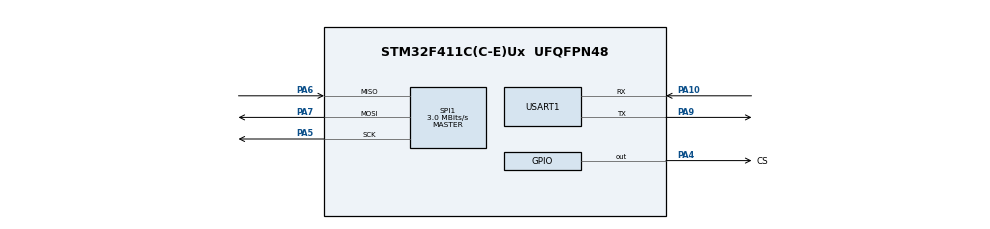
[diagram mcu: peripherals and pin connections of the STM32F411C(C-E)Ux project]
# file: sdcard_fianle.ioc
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Dma.Request0=SPI1_RX
Dma.Request1=SPI1_TX
Dma.SPI1_RX.0.Direction=DMA_PERIPH_TO_MEMORY
Dma.SPI1_RX.0.FIFOMode=DMA_FIFOMODE_DISABLE
Dma.SPI1_RX.0.Instance=DMA2_Stream0
Dma.SPI1_RX.0.MemDataAlignment=DMA_MDATAALIGN_BYTE
Dma.SPI1_RX.0.MemInc=DMA_MINC_ENABLE
Dma.SPI1_RX.0.Mode=DMA_NORMAL
Dma.SPI1_RX.0.PeriphDataAlignment=DMA_PDATAALIGN_BYTE
Dma.SPI1_RX.0.PeriphInc=DMA_PINC_DISABLE
Dma.SPI1_RX.0.Priority=DMA_PRIORITY_LOW
Dma.SPI1_TX.1.Direction=DMA_MEMORY_TO_PERIPH
Dma.SPI1_TX.1.FIFOMode=DMA_FIFOMODE_DISABLE
Dma.SPI1_TX.1.Instance=DMA2_Stream2
Dma.SPI1_TX.1.MemDataAlignment=DMA_MDATAALIGN_BYTE
Dma.SPI1_TX.1.MemInc=DMA_MINC_ENABLE
Dma.SPI1_TX.1.Mode=DMA_NORMAL
Dma.SPI1_TX.1.PeriphDataAlignment=DMA_PDATAALIGN_BYTE
Dma.SPI1_TX.1.PeriphInc=DMA_PINC_DISABLE
Dma.SPI1_TX.1.Priority=DMA_PRIORITY_LOW
FATFS._USE_LABEL=1
FATFS._USE_LFN=3
Mcu.Family=STM32F4
Mcu.Name=STM32F411C(C-E)Ux
Mcu.Package=UFQFPN48
NVIC.DMA2_Stream0_IRQn=true\:0\:0\:false\:false\:true\:false\:true\:true
NVIC.DMA2_Stream2_IRQn=true\:0\:0\:false\:false\:true\:false\:true\:true
NVIC.PriorityGroup=NVIC_PRIORITYGROUP_4
PA10.Mode=Asynchronous
PA10.Signal=USART1_RX
PA4.GPIO_Label=CS
PA4.GPIO_Speed=GPIO_SPEED_FREQ_HIGH
PA4.PinState=GPIO_PIN_SET
PA4.Signal=GPIO_Output
PA5.Mode=Full_Duplex_Master
PA5.Signal=SPI1_SCK
PA6.Mode=Full_Duplex_Master
PA6.Signal=SPI1_MISO
PA7.Mode=Full_Duplex_Master
PA7.Signal=SPI1_MOSI
PA9.Mode=Asynchronous
PA9.Signal=USART1_TX
PH0\ -\ OSC_IN.Mode=HSE-External-Oscillator
PH0\ -\ OSC_IN.Signal=RCC_OSC_IN
PH1\ -\ OSC_OUT.Mode=HSE-External-Oscillator
PH1\ -\ OSC_OUT.Signal=RCC_OSC_OUT
ProjectManager.HeapSize=0x200
ProjectManager.StackSize=0x400
ProjectManager.TargetToolchain=STM32CubeIDE
RCC.48MHZClocksFreq_Value=48000000
RCC.AHBFreq_Value=96000000
RCC.APB1CLKDivider=RCC_HCLK_DIV2
RCC.APB1Freq_Value=48000000
RCC.APB1TimFreq_Value=96000000
RCC.APB2Freq_Value=96000000
RCC.APB2TimFreq_Value=96000000
RCC.CortexFreq_Value=96000000
RCC.HCLKFreq_Value=96000000
RCC.HSE_VALUE=25000000
RCC.HSI_VALUE=16000000
RCC.LSE_VALUE=32768
RCC.PLLM=8
RCC.PLLN=96
RCC.SYSCLKFreq_VALUE=96000000
RCC.SYSCLKSource=RCC_SYSCLKSOURCE_PLLCLK
RCC.VCOOutputFreq_Value=192000000
SPI1.BaudRatePrescaler=SPI_BAUDRATEPRESCALER_32
SPI1.CalculateBaudRate=3.0 MBits/s
SPI1.Direction=SPI_DIRECTION_2LINES
SPI1.Mode=SPI_MODE_MASTER
SPI1.VirtualType=VM_MASTER
USART1.VirtualMode=VM_ASYNC
VP_FATFS_VS_Generic.Mode=User_defined
board=custom

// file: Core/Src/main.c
/* USER CODE BEGIN Header */
/**
  ******************************************************************************
  * @file           : main.c
  * @brief          : Main program body
  ******************************************************************************
  * @attention
  *
  * Copyright (c) 2026 STMicroelectronics.
  * All rights reserved.
  *
  * This software is licensed under terms that can be found in the LICENSE file
  * in the root directory of this software component.
  * If no LICENSE file comes with this software, it is provided AS-IS.
  *
  ******************************************************************************
  */
/* USER CODE END Header */
#include "main.h"
#include "fatfs.h"

/* USER CODE BEGIN Includes */
#include "sd_functions.h"
#include "stdio.h"
/* USER CODE END Includes */

SPI_HandleTypeDef hspi1;
DMA_HandleTypeDef hdma_spi1_rx;
DMA_HandleTypeDef hdma_spi1_tx;

UART_HandleTypeDef huart1;

/* USER CODE BEGIN PV */
uint8_t bufr[80];
UINT br;
/* USER CODE END PV */

void SystemClock_Config(void);
static void MX_GPIO_Init(void);
static void MX_DMA_Init(void);
static void MX_SPI1_Init(void);
static void MX_USART1_UART_Init(void);

/* USER CODE BEGIN 0 */
int _write(int fd, unsigned char *buf, int len) {
  if (fd == 1 || fd == 2) {
    HAL_UART_Transmit(&huart1, buf, len, 999);
  }
  return len;
}
/* USER CODE END 0 */

int main(void)
{

  /* MCU Configuration--------------------------------------------------------*/

  /* Reset of all peripherals, Initializes the Flash interface and the Systick. */
  HAL_Init();

  /* Configure the system clock */
  SystemClock_Config();

  /* Initialize all configured peripherals */
  MX_GPIO_Init();
  MX_DMA_Init();
  MX_SPI1_Init();
  MX_USART1_UART_Init();
  //MX_FATFS_Init();
  /* USER CODE BEGIN 2 */
  /* USER CODE BEGIN 2 */

//  sd_mount();
//  sd_write_file("iwannaread.txt", "IM FREE FINALLY THIS WORKED YAY");
//  sd_read_file("iwannaread.txt", bufr, sizeof(bufr) - 1, &br);
//  bufr[br] = '\0';
//  printf("Read back: %s\n", bufr);
//  sd_unmount();

  sd_mount();
  sd_write_file("iwannaread_1.txt", "IM FREE FINALLY THIS WORKED YAY");

  if (sd_read_file("iwannaread.txt", bufr, sizeof(bufr) - 1, &br) == 0) {
      bufr[br] = '\0';
      printf("Read back: %s\n", bufr);
  } else {
      printf("Read FAILED\n");
  }

  sd_unmount();
    /* USER CODE END 2 */
  /* USER CODE END 2 */

  /* Infinite loop */
  while (1)
  {

  }
}

void SystemClock_Config(void)
{
  RCC_OscInitTypeDef RCC_OscInitStruct = {0};
  RCC_ClkInitTypeDef RCC_ClkInitStruct = {0};

  /** Configure the main internal regulator output voltage
  */
  __HAL_RCC_PWR_CLK_ENABLE();
  __HAL_PWR_VOLTAGESCALING_CONFIG(PWR_REGULATOR_VOLTAGE_SCALE1);

  /** Initializes the RCC Oscillators according to the specified parameters
  * in the RCC_OscInitTypeDef structure.
  */
  RCC_OscInitStruct.OscillatorType = RCC_OSCILLATORTYPE_HSE;
  RCC_OscInitStruct.HSEState = RCC_HSE_ON;
  RCC_OscInitStruct.PLL.PLLState = RCC_PLL_ON;
  RCC_OscInitStruct.PLL.PLLSource = RCC_PLLSOURCE_HSE;
  RCC_OscInitStruct.PLL.PLLM = 8;
  RCC_OscInitStruct.PLL.PLLN = 96;
  RCC_OscInitStruct.PLL.PLLP = RCC_PLLP_DIV2;
  RCC_OscInitStruct.PLL.PLLQ = 4;
  if (HAL_RCC_OscConfig(&RCC_OscInitStruct) != HAL_OK)
  {
    Error_Handler();
  }

  /** Initializes the CPU, AHB and APB buses clocks
  */
  RCC_ClkInitStruct.ClockType = RCC_CLOCKTYPE_HCLK|RCC_CLOCKTYPE_SYSCLK
                              |RCC_CLOCKTYPE_PCLK1|RCC_CLOCKTYPE_PCLK2;
  RCC_ClkInitStruct.SYSCLKSource = RCC_SYSCLKSOURCE_PLLCLK;
  RCC_ClkInitStruct.AHBCLKDivider = RCC_SYSCLK_DIV1;
  RCC_ClkInitStruct.APB1CLKDivider = RCC_HCLK_DIV2;
  RCC_ClkInitStruct.APB2CLKDivider = RCC_HCLK_DIV1;

  if (HAL_RCC_ClockConfig(&RCC_ClkInitStruct, FLASH_LATENCY_3) != HAL_OK)
  {
    Error_Handler();
  }
}

static void MX_SPI1_Init(void)
{

  /* SPI1 parameter configuration*/
  hspi1.Instance = SPI1;
  hspi1.Init.Mode = SPI_MODE_MASTER;
  hspi1.Init.Direction = SPI_DIRECTION_2LINES;
  hspi1.Init.DataSize = SPI_DATASIZE_8BIT;
  hspi1.Init.CLKPolarity = SPI_POLARITY_LOW;
  hspi1.Init.CLKPhase = SPI_PHASE_1EDGE;
  hspi1.Init.NSS = SPI_NSS_SOFT;
  hspi1.Init.BaudRatePrescaler = SPI_BAUDRATEPRESCALER_32;
  hspi1.Init.FirstBit = SPI_FIRSTBIT_MSB;
  hspi1.Init.TIMode = SPI_TIMODE_DISABLE;
  hspi1.Init.CRCCalculation = SPI_CRCCALCULATION_DISABLE;
  hspi1.Init.CRCPolynomial = 10;
  if (HAL_SPI_Init(&hspi1) != HAL_OK)
  {
    Error_Handler();
  }

}

static void MX_USART1_UART_Init(void)
{

  huart1.Instance = USART1;
  huart1.Init.BaudRate = 115200;
  huart1.Init.WordLength = UART_WORDLENGTH_8B;
  huart1.Init.StopBits = UART_STOPBITS_1;
  huart1.Init.Parity = UART_PARITY_NONE;
  huart1.Init.Mode = UART_MODE_TX_RX;
  huart1.Init.HwFlowCtl = UART_HWCONTROL_NONE;
  huart1.Init.OverSampling = UART_OVERSAMPLING_16;
  if (HAL_UART_Init(&huart1) != HAL_OK)
  {
    Error_Handler();
  }

}

static void MX_DMA_Init(void)
{

  /* DMA controller clock enable */
  __HAL_RCC_DMA2_CLK_ENABLE();

  /* DMA interrupt init */
  /* DMA2_Stream0_IRQn interrupt configuration */
  HAL_NVIC_SetPriority(DMA2_Stream0_IRQn, 0, 0);
  HAL_NVIC_EnableIRQ(DMA2_Stream0_IRQn);
  /* DMA2_Stream2_IRQn interrupt configuration */
  HAL_NVIC_SetPriority(DMA2_Stream2_IRQn, 0, 0);
  HAL_NVIC_EnableIRQ(DMA2_Stream2_IRQn);

}

static void MX_GPIO_Init(void)
{
  GPIO_InitTypeDef GPIO_InitStruct = {0};

  /* GPIO Ports Clock Enable */
  __HAL_RCC_GPIOH_CLK_ENABLE();
  __HAL_RCC_GPIOA_CLK_ENABLE();

  /*Configure GPIO pin Output Level */
  HAL_GPIO_WritePin(CS_GPIO_Port, CS_Pin, GPIO_PIN_SET);

  /*Configure GPIO pin : CS_Pin */
  GPIO_InitStruct.Pin = CS_Pin;
  GPIO_InitStruct.Mode = GPIO_MODE_OUTPUT_PP;
  GPIO_InitStruct.Pull = GPIO_NOPULL;
  GPIO_InitStruct.Speed = GPIO_SPEED_FREQ_HIGH;
  HAL_GPIO_Init(CS_GPIO_Port, &GPIO_InitStruct);

}

void Error_Handler(void)
{
  __disable_irq();
  while (1)
  {
  }
}
